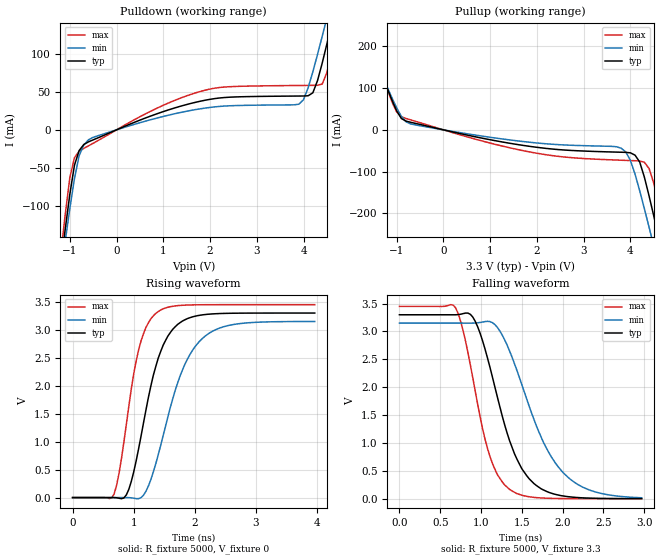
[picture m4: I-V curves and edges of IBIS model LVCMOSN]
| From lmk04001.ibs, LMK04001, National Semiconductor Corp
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|   Model LVCMOSN
[Model]  LVCMOSN
Model_type Output
Polarity   Inverting
Vmeas =  1.65V
Rref =   50.0000
Vref =   1.65V
C_comp   1.3000pF   NA   NA
[Temperature Range]   25.0000   85.0000   -40.0000
[Voltage Range]   3.3000V   3.1500V   3.4500V
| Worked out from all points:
|   slope of the pulldown table from 0 to 0.495 V, typ, clamps not added: 39.1 ohm
|   slope of the pullup table from 0 to 0.495 V, typ, clamps not added: 40.4 ohm
|   rising waveform, R_fixture 5000, V_fixture 0: 20-80 % time 410ps typ, 533ps min, 311ps max; typ from 0 V to 3.3 V
|   falling waveform, R_fixture 5000, V_fixture 3.3: 20-80 % time 400ps typ, 526ps min, 306ps max; typ from 3.3 V to 0 V
[Pulldown]
|Voltage   I(typ)   I(min)   I(max)
-3.3V     -1.357A    -1.246A    -1.518A
-1.2V     -181.8mA   -193.5mA   -168.5mA
-1.1V     -132mA     -147.7mA   -112.6mA
-900mV    -46.51mA   -64.09mA   -36.69mA
-600mV    -15.8mA    -13.08mA   -21.07mA
1.8V      37.8mA     27.77mA    50.67mA
3.9V      44.52mA    33.75mA    58.41mA
4.2V      48.77mA    76.48mA    58.59mA
4.5V      113.1mA    147.5mA    75.47mA
4.6V      139.3mA    172.4mA    101.3mA
4.8V      193.6mA    225.6mA    159.7mA
6.5V      748.4mA    724.5mA    787mA
[Pullup]
|Voltage   I(typ)   I(min)   I(max)
-3.3V     783.8mA    709.6mA    825.3mA
-1.7V     250.6mA    238.9mA    267mA
-1V       45.55mA    52.6mA     42.93mA
-700mV    18.09mA    14.13mA    23.87mA
1.8V      -38.81mA   -29.18mA   -51.94mA
3.8V      -53.62mA   -43.82mA   -72.76mA
4V        -55.05mA   -72.98mA   -73.57mA
4.2V      -77.23mA   -146.2mA   -74.51mA
4.5V      -206.1mA   -278.3mA   -127.8mA
4.6V      -255.3mA   -324mA     -177.6mA
4.8V      -356.1mA   -417.1mA   -287.9mA
6.5V      -1.305A    -1.248A    -1.356A
[Ramp]
| variable   typ   min   max
dV/dt_r  1.9858/411.52p   1.8870/534.30p   2.0688/310.71p
dV/dt_f  1.9858/401.11p   1.8870/533.17p   2.0688/304.10p
R_load = 50.00
[Rising Waveform]
R_fixture= 5000
V_fixture= 0
V_fixture_min= 0
V_fixture_max= 0
|time   V(typ)   V(min)   V(max)
0s        1.87uV     2.13uV     1.614uV
680ps     194.6uV    -21.12uV   66.83mV
760ps     -11.43mV   55.75uV    434.4mV
920ps     147.1mV    -871.5uV   1.632V
1.12ns    1.101V     -1.119mV   2.804V
1.36ns    2.341V     602.6mV    3.294V
1.56ns    2.891V     1.45V      3.403V
1.76ns    3.13V      2.182V     3.437V
2.16ns    3.272V     2.881V     3.449V
3.96ns    3.3V       3.149V     3.45V
|4.0E-9   3.3000   3.1495   3.4500
[Falling Waveform]
R_fixture= 5000
V_fixture= 3.3
V_fixture_min= 3.15
V_fixture_max= 3.45
|time   V(typ)   V(min)   V(max)
0s        3.3V       3.15V      3.45V
690ps     3.3V       3.15V      3.42V
810ps     3.33V      3.15V      2.83V
960ps     3.082V     3.156V     1.688V
1.14ns    2.184V     3.159V     633mV
1.35ns    1.043V     2.652V     167.8mV
1.59ns    358.5mV    1.663V     34.51mV
2.01ns    48.26mV    462.2mV    2.128mV
2.4ns     7.178mV    122mV      164.5uV
2.97ns    447.9uV    16.38mV    5.603uV
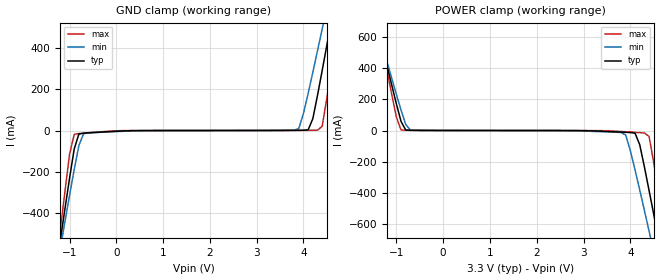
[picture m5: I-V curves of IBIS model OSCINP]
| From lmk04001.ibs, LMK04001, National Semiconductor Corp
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|   Model OSCINP
[Model]  OSCINP
Model_type Input
Polarity   Non-Inverting
Vinl =   -150m
Vinh =   +150m
C_comp   1.4200pF   NA   NA
[Temperature Range]   25.0000   85.0000   -40.0000
[Voltage Range]   3.3000V   3.1500V   3.4500V
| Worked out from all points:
|   POWER clamp passes 1 mA (typ) near -0.58 V on its own axis
[GND_clamp]
|Voltage   I(typ)   I(min)   I(max)
-3.3V     -3.88A     -3.437A    -4.6A
-1.2V     -537.6mA   -577.7mA   -489.1mA
-1V       -232.8mA   -315.7mA   -116.7mA
-900mV    -90.1mA    -189.6mA   -18.68mA
-600mV    -11.33mA   -11.41mA   -10.65mA
3.9V      1.034mA    9.809mA    759.3uA
4.1V      3.301mA    180.4mA    1.067mA
4.3V      170.8mA    387.4mA    1.606mA
4.4V      291.5mA    493mA      20.73mA
4.6V      539mA      705.5mA    307.8mA
4.8V      788.9mA    919.1mA    615.1mA
6.5V      2.922A     2.741A     3.248A
[POWER_clamp]
|Voltage   I(typ)   I(min)   I(max)
-3.3V     3.047A     2.687A     3.402A
-1.4V     663.8mA    652.2mA    692.4mA
-900mV    57.55mA    130.8mA    3.364mA
-700mV    1.241mA    3.059mA    1.164mA
3.8V      -9.967mA   -12.53mA   -6.287mA
3.9V      -11.33mA   -28.54mA   -7.984mA
4.1V      -17.1mA    -252mA     -11.63mA
4.3V      -232.8mA   -511.4mA   -15.83mA
4.4V      -383.7mA   -644.4mA   -37.63mA
4.6V      -693.6mA   -913.8mA   -394.1mA
4.8V      -1.01A     -1.185A    -777.2mA
6.5V      -3.72A     -3.437A    -4.109A
